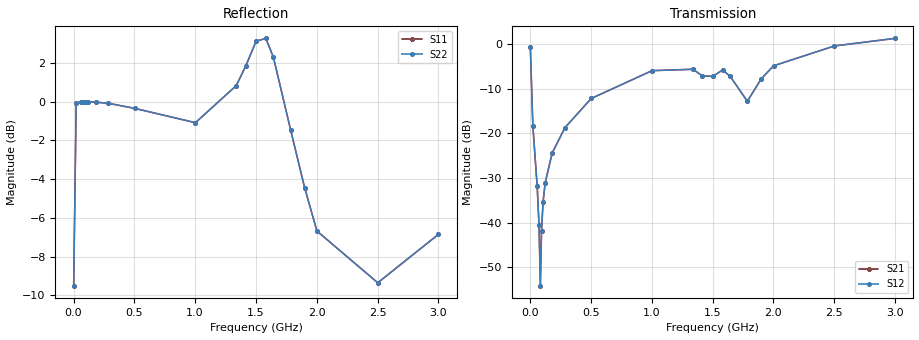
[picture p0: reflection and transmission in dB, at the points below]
!s-Parameter Generated by FASTRON Sdn. Bhd.
!FASTRON P/N : MICC-5R6X
!Keysight Technologies,E4991B,MY54100416,A.01.15
!Date: Fri Aug 28 10:45:12 2026
!Version  : Rev00 Fri Aug 28 10:45:12 2026
!Data & Calibration Information:
!PortZ  Port1:50+j0  Port2:50+j0
!When reading, reference impedance value at option line is always used.
! Remarks : This data is being provided solely for informational purposes.
!Freq	S11	S21	S12	S22
# Hz S dB R 50
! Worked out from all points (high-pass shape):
!   1601 points, 1 MHz to 3 GHz, reference 50 ohm
!   highest |S21| = 1.32 dB at 3 GHz (marker M1); lowest = -54.1 dB at 83.47 MHz (marker M2)
!   |S21| within 3 dB of the highest: start of sweep to 1.777 MHz; 2.29 GHz to end of sweep
!   lowest |S11| = -9.5 dB at 1 MHz (marker M3), VSWR 2.01, Z = 50.9 + j35.9 ohm
!   |S11| at or under -10 dB: nowhere
!   |S22| runs from -9.5 to 3.4 dB; largest |S21 - S12| = 0
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1000000  -9.50 69.0  -0.60 -19.6  -0.60 -19.6  -9.50 69.0
2.161812e7  -0.08 7.0  -18.30 -82.0  -18.30 -82.0  -0.08 7.0
5.723125e7  -0.02 1.5  -31.85 -84.7  -31.85 -84.7  -0.02 1.5
7.222625e7  -0.02 0.5  -40.46 -77.8  -40.46 -77.8  -0.02 0.5
8.34725e7  -0.02 -0.0  -54.13 17.2  -54.13 17.2  -0.02 -0.0
9.284438e7  -0.02 -0.5  -41.81 75.9  -41.81 75.9  -0.02 -0.5
1.05965e8  -0.02 -1.0  -35.28 82.7  -35.28 82.7  -0.02 -1.0
1.228344e8  -0.02 -1.6  -31.07 84.7  -31.07 84.7  -0.02 -1.6
1.8094e8  -0.03 -3.5  -24.35 84.6  -24.35 84.6  -0.03 -3.5
2.85905e8  -0.09 -6.7  -18.68 81.7  -18.68 81.7  -0.09 -6.7
5.014581e8  -0.35 -14.3  -12.16 73.7  -12.16 73.7  -0.35 -14.3
1.001916e9  -1.09 -30.4  -5.92 61.9  -5.92 61.9  -1.09 -30.4
1.337429e9  0.82 -28.4  -5.61 86.4  -5.61 86.4  0.82 -28.4
1.414279e9  1.81 -19.6  -7.06 111.2  -7.06 111.2  1.81 -19.6
1.5005e9  3.11 -3.4  -7.22 168.9  -7.22 168.9  3.11 -3.4
1.581098e9  3.26 11.3  -5.77 -146.2  -5.77 -146.2  3.26 11.3
1.642952e9  2.29 16.0  -7.16 -124.9  -7.16 -124.9  2.29 16.0
1.785405e9  -1.48 10.5  -12.78 -41.8  -12.78 -41.8  -1.48 10.5
1.899742e9  -4.44 -6.7  -7.73 9.8  -7.73 9.8  -4.44 -6.7
2.000958e9  -6.68 -17.1  -4.83 13.8  -4.83 13.8  -6.68 -17.1
2.501416e9  -9.35 -73.0  -0.38 19.9  -0.38 19.9  -9.35 -73.0
3e9  -6.85 -99.4  1.32 22.7  1.32 22.7  -6.85 -99.4
